VERSION 5.8 ;
BUSBITCHARS "[]" ;
DIVIDERCHAR "/" ;

UNITS
  DATABASE MICRONS 2000 ;
END UNITS

# A TSV-like bridge cell. Each power pin has one shape on backside B1 and
# another on frontside M1. LEF58_BACKSIDE_BRIDGE tells PSM that these two
# surfaces are electrically connected through the cell.
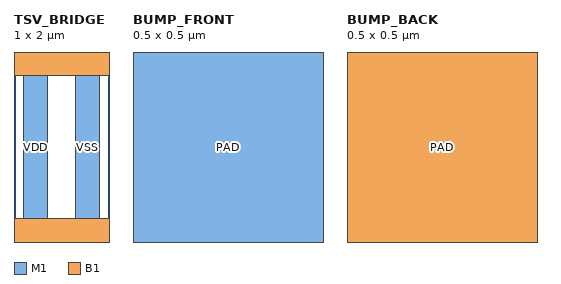
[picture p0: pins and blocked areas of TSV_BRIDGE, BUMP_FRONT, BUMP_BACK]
MACRO TSV_BRIDGE
  CLASS CORE ;
  ORIGIN 0 0 ;
  SIZE 1.000 BY 2.000 ;
  SYMMETRY X Y ;
  PROPERTY LEF58_BACKSIDE_BRIDGE "BACKSIDEBRIDGE ;" ;
  PIN VDD
    DIRECTION INOUT ;
    USE POWER ;
    PORT
      LAYER M1 ;
        RECT 0.100 0.100 0.350 1.900 ;
    END
    PORT
      LAYER B1 ;
        RECT 0.000 1.750 1.000 2.000 ;
    END
  END VDD
  PIN VSS
    DIRECTION INOUT ;
    USE GROUND ;
    PORT
      LAYER M1 ;
        RECT 0.650 0.100 0.900 1.900 ;
    END
    PORT
      LAYER B1 ;
        RECT 0.000 0.000 1.000 0.250 ;
    END
  END VSS
END TSV_BRIDGE

# Frontside micro-bump used at the Chip A/Chip B bond interface.
MACRO BUMP_FRONT
  CLASS COVER BUMP ;
  ORIGIN 0 0 ;
  SIZE 0.500 BY 0.500 ;
  SYMMETRY X Y ;
  PIN PAD
    DIRECTION INOUT ;
    USE SIGNAL ;
    PORT
      LAYER M1 ;
        RECT 0.000 0.000 0.500 0.500 ;
    END
  END PAD
END BUMP_FRONT

# Backside package bump used to show where supply enters Chip A.
MACRO BUMP_BACK
  CLASS COVER BUMP ;
  ORIGIN 0 0 ;
  SIZE 0.500 BY 0.500 ;
  SYMMETRY X Y ;
  PIN PAD
    DIRECTION INOUT ;
    USE SIGNAL ;
    PORT
      LAYER B1 ;
        RECT 0.000 0.000 0.500 0.500 ;
    END
  END PAD
END BUMP_BACK

END LIBRARY
